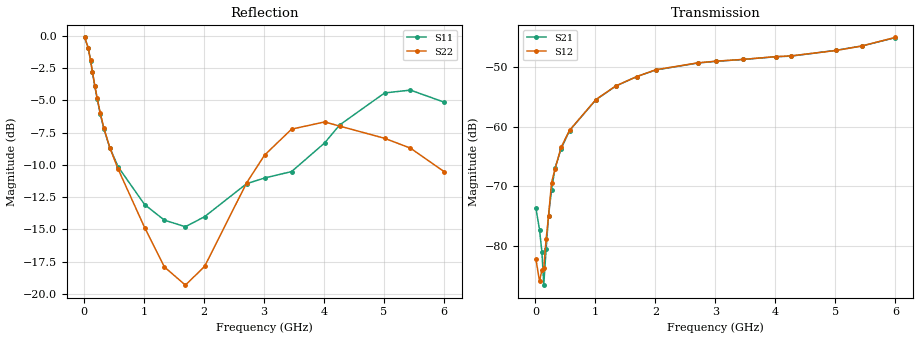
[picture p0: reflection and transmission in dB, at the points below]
!Agilent Technologies,N5230A,MY45001650,A.07.50.48
!Agilent N5230A: A.07.50.48
!Date: Saturday, July 08, 2017 15:43:29
!Correction: S11(Full 2 Port(1,2))
!S21(Full 2 Port(1,2))
!S12(Full 2 Port(1,2))
!S22(Full 2 Port(1,2))
!S2P File: Measurements: S11, S21, S12, S22:
# Hz S  dB  R 50
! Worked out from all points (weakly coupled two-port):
!   600 points, 10 MHz to 6 GHz, reference 50 ohm
!   highest |S21| = -45.10 dB at 6 GHz (marker M1); lowest = -86.5 dB at 140 MHz (marker M2)
!   lowest |S11| = -14.8 dB at 1.69 GHz (marker M3), VSWR 1.44, Z = 34.6 + j1.18 ohm
!   |S11| at or under -10 dB: 553.8 MHz to 3.664 GHz (3.11 GHz wide, 147 % of centre)
!   |S22| runs from -19.5 to -0.1 dB; largest |S21 - S12| = 0.00014
!   S11 on the Smith chart (normalised r, x): 10 MHz: 3, -20; 110 MHz: 0.52, -1.89; 330 MHz: 0.55, -0.56; 2.71 GHz: 0.59, +0.09; 4.26 GHz: 1.38, +1.12; 6 GHz: 2.60, -1.43
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1e7  -0.11 -5.7  -73.69 85.6  -82.20 60.7  -0.11 -5.7
7e7  -0.91 -36.4  -77.27 52.3  -85.89 117.5  -0.91 -36.4
1.1e8  -1.91 -53.1  -81.04 20.1  -84.00 -28.3  -1.90 -53.0
1.4e8  -2.77 -63.8  -86.53 79.5  -83.67 -177.9  -2.76 -63.7
1.8e8  -3.88 -76.0  -80.45 112.0  -78.84 125.5  -3.86 -76.1
2.2e8  -4.86 -86.2  -74.91 108.9  -74.91 114.3  -4.83 -86.4
2.7e8  -6.02 -97.4  -70.57 107.8  -69.38 103.3  -5.95 -97.5
3.3e8  -7.18 -109.0  -66.87 92.8  -67.03 92.9  -7.13 -108.2
4.3e8  -8.67 -124.9  -63.69 76.3  -63.44 76.4  -8.66 -123.5
5.7e8  -10.16 -142.1  -60.65 59.5  -60.62 59.0  -10.34 -139.5
1.01e9  -13.08 -172.4  -55.50 14.2  -55.46 14.1  -14.86 -167.6
1.34e9  -14.29 175.1  -53.21 -17.6  -53.19 -17.5  -17.92 -179.5
1.69e9  -14.80 174.8  -51.62 -50.4  -51.62 -50.5  -19.33 -176.2
2.01e9  -14.02 176.9  -50.51 -80.7  -50.47 -80.6  -17.88 -174.5
2.71e9  -11.46 164.7  -49.35 -147.9  -49.32 -148.0  -11.40 160.8
3.01e9  -11.02 149.6  -49.07 -176.3  -49.04 -176.3  -9.24 148.3
3.46e9  -10.52 117.0  -48.75 139.4  -48.75 139.5  -7.23 132.2
4.01e9  -8.30 64.1  -48.30 86.3  -48.28 86.3  -6.67 109.5
4.26e9  -6.91 46.2  -48.20 63.4  -48.16 63.5  -6.99 97.9
5.01e9  -4.42 12.9  -47.23 0.5  -47.25 0.7  -7.94 53.0
5.44e9  -4.20 0.3  -46.50 -33.4  -46.50 -33.5  -8.70 24.0
6e9  -5.13 -20.2  -45.10 -75.9  -45.06 -75.8  -10.52 -9.5
